VERSION 5.8 ;
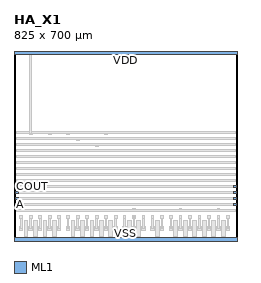
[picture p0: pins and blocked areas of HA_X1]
MACRO HA_X1
  CLASS CORE ;
  ORIGIN 0 0 ;
  SIZE 825 BY 700 ;
  SITE ICPS2023_5_ROW700 ;
  PIN A
    DIRECTION INPUT ;
    USE SIGNAL ;
    PORT
      LAYER ML1 ;
        RECT 5 130 15 140 ;
        RECT 810 130 820 140 ;
    END
  END A
  PIN B
    DIRECTION INPUT ;
    USE SIGNAL ;
    PORT
      LAYER ML1 ;
        RECT 5 152 15 162 ;
        RECT 810 152 820 162 ;
    END
  END B
  PIN SUM
    DIRECTION OUTPUT ;
    USE SIGNAL ;
    PORT
      LAYER ML1 ;
        RECT 5 174 15 184 ;
        RECT 810 174 820 184 ;
    END
  END SUM
  PIN COUT
    DIRECTION OUTPUT ;
    USE SIGNAL ;
    PORT
      LAYER ML1 ;
        RECT 5 196 15 206 ;
        RECT 810 196 820 206 ;
    END
  END COUT
  PIN VDD
    DIRECTION INOUT ;
    USE POWER ;
    PORT
      LAYER ML1 ;
        RECT 0 688 825 700 ;
    END
  END VDD
  PIN VSS
    DIRECTION INOUT ;
    USE GROUND ;
    PORT
      LAYER ML1 ;
        RECT 0 0 825 12 ;
    END
  END VSS
  OBS
    LAYER ML1 ;
      RECT 20 39.5 33 52.5 ;
      RECT 55 39.5 68 52.5 ;
      RECT 90 39.5 103 52.5 ;
      RECT 125 39.5 138 52.5 ;
      RECT 160 39.5 173 52.5 ;
      RECT 37.5 16 50.5 29 ;
      RECT 37.5 63 50.5 76 ;
      RECT 37 16 51 76 ;
      RECT 72.5 16 85.5 29 ;
      RECT 72.5 63 85.5 76 ;
      RECT 72 16 86 76 ;
      RECT 107.5 16 120.5 29 ;
      RECT 107.5 63 120.5 76 ;
      RECT 107 16 121 76 ;
      RECT 142.5 16 155.5 29 ;
      RECT 142.5 63 155.5 76 ;
      RECT 142 16 156 76 ;
      RECT 23.5 46 29.5 89 ;
      RECT 21.5 84 31.5 94 ;
      RECT 21.5 196 31.5 206 ;
      RECT 58.5 46 64.5 89 ;
      RECT 56.5 84 66.5 94 ;
      RECT 56.5 394 66.5 404 ;
      RECT 93.5 46 99.5 89 ;
      RECT 91.5 84 101.5 94 ;
      RECT 91.5 240 101.5 250 ;
      RECT 128.5 46 134.5 89 ;
      RECT 126.5 84 136.5 94 ;
      RECT 126.5 394 136.5 404 ;
      RECT 163.5 46 169.5 89 ;
      RECT 161.5 84 171.5 94 ;
      RECT 161.5 306 171.5 316 ;
      RECT 39 240 49 250 ;
      RECT 74 130 84 140 ;
      RECT 109 152 119 162 ;
      RECT 144 130 154 140 ;
      RECT 193 39.5 206 52.5 ;
      RECT 228 39.5 241 52.5 ;
      RECT 263 39.5 276 52.5 ;
      RECT 298 39.5 311 52.5 ;
      RECT 333 39.5 346 52.5 ;
      RECT 368 39.5 381 52.5 ;
      RECT 210.5 16 223.5 29 ;
      RECT 210.5 63 223.5 76 ;
      RECT 210 16 224 76 ;
      RECT 245.5 16 258.5 29 ;
      RECT 245.5 63 258.5 76 ;
      RECT 245 16 259 76 ;
      RECT 280.5 16 293.5 29 ;
      RECT 280.5 63 293.5 76 ;
      RECT 280 16 294 76 ;
      RECT 315.5 16 328.5 29 ;
      RECT 315.5 63 328.5 76 ;
      RECT 315 16 329 76 ;
      RECT 350.5 16 363.5 29 ;
      RECT 350.5 63 363.5 76 ;
      RECT 350 16 364 76 ;
      RECT 196.5 46 202.5 89 ;
      RECT 194.5 84 204.5 94 ;
      RECT 194.5 394 204.5 404 ;
      RECT 231.5 46 237.5 89 ;
      RECT 229.5 84 239.5 94 ;
      RECT 229.5 372 239.5 382 ;
      RECT 266.5 46 272.5 89 ;
      RECT 264.5 84 274.5 94 ;
      RECT 264.5 174 274.5 184 ;
      RECT 301.5 46 307.5 89 ;
      RECT 299.5 84 309.5 94 ;
      RECT 299.5 350 309.5 360 ;
      RECT 336.5 46 342.5 89 ;
      RECT 334.5 84 344.5 94 ;
      RECT 334.5 394 344.5 404 ;
      RECT 371.5 46 377.5 89 ;
      RECT 369.5 84 379.5 94 ;
      RECT 369.5 328 379.5 338 ;
      RECT 212 306 222 316 ;
      RECT 247 152 257 162 ;
      RECT 282 328 292 338 ;
      RECT 317 130 327 140 ;
      RECT 352 152 362 162 ;
      RECT 401 39.5 414 52.5 ;
      RECT 436 39.5 449 52.5 ;
      RECT 471 39.5 484 52.5 ;
      RECT 418.5 16 431.5 29 ;
      RECT 418.5 63 431.5 76 ;
      RECT 418 16 432 76 ;
      RECT 453.5 16 466.5 29 ;
      RECT 453.5 63 466.5 76 ;
      RECT 453 16 467 76 ;
      RECT 404.5 46 410.5 89 ;
      RECT 402.5 84 412.5 94 ;
      RECT 402.5 196 412.5 206 ;
      RECT 439.5 46 445.5 89 ;
      RECT 437.5 84 447.5 94 ;
      RECT 437.5 108 447.5 118 ;
      RECT 474.5 46 480.5 89 ;
      RECT 472.5 84 482.5 94 ;
      RECT 472.5 218 482.5 228 ;
      RECT 420 240 430 250 ;
      RECT 455 152 465 162 ;
      RECT 504 39.5 517 52.5 ;
      RECT 539 39.5 552 52.5 ;
      RECT 521.5 16 534.5 29 ;
      RECT 521.5 63 534.5 76 ;
      RECT 521 16 535 76 ;
      RECT 507.5 46 513.5 89 ;
      RECT 505.5 84 515.5 94 ;
      RECT 505.5 218 515.5 228 ;
      RECT 542.5 46 548.5 89 ;
      RECT 540.5 84 550.5 94 ;
      RECT 540.5 240 550.5 250 ;
      RECT 523 130 533 140 ;
      RECT 572 39.5 585 52.5 ;
      RECT 607 39.5 620 52.5 ;
      RECT 642 39.5 655 52.5 ;
      RECT 677 39.5 690 52.5 ;
      RECT 712 39.5 725 52.5 ;
      RECT 747 39.5 760 52.5 ;
      RECT 782 39.5 795 52.5 ;
      RECT 589.5 16 602.5 29 ;
      RECT 589.5 63 602.5 76 ;
      RECT 589 16 603 76 ;
      RECT 624.5 16 637.5 29 ;
      RECT 624.5 63 637.5 76 ;
      RECT 624 16 638 76 ;
      RECT 659.5 16 672.5 29 ;
      RECT 659.5 63 672.5 76 ;
      RECT 659 16 673 76 ;
      RECT 694.5 16 707.5 29 ;
      RECT 694.5 63 707.5 76 ;
      RECT 694 16 708 76 ;
      RECT 729.5 16 742.5 29 ;
      RECT 729.5 63 742.5 76 ;
      RECT 729 16 743 76 ;
      RECT 764.5 16 777.5 29 ;
      RECT 764.5 63 777.5 76 ;
      RECT 764 16 778 76 ;
      RECT 575.5 46 581.5 89 ;
      RECT 573.5 84 583.5 94 ;
      RECT 573.5 306 583.5 316 ;
      RECT 610.5 46 616.5 89 ;
      RECT 608.5 84 618.5 94 ;
      RECT 608.5 108 618.5 118 ;
      RECT 645.5 46 651.5 89 ;
      RECT 643.5 84 653.5 94 ;
      RECT 643.5 262 653.5 272 ;
      RECT 680.5 46 686.5 89 ;
      RECT 678.5 84 688.5 94 ;
      RECT 678.5 174 688.5 184 ;
      RECT 715.5 46 721.5 89 ;
      RECT 713.5 84 723.5 94 ;
      RECT 713.5 284 723.5 294 ;
      RECT 750.5 46 756.5 89 ;
      RECT 748.5 84 758.5 94 ;
      RECT 748.5 108 758.5 118 ;
      RECT 785.5 46 791.5 89 ;
      RECT 783.5 84 793.5 94 ;
      RECT 783.5 328 793.5 338 ;
      RECT 591 130 601 140 ;
      RECT 626 152 636 162 ;
      RECT 661 130 671 140 ;
      RECT 696 306 706 316 ;
      RECT 731 328 741 338 ;
      RECT 766 152 776 162 ;
      RECT 10 110 815 116 ;
      RECT 10 132 815 138 ;
      RECT 10 154 815 160 ;
      RECT 10 176 815 182 ;
      RECT 10 198 815 204 ;
      RECT 10 220 815 226 ;
      RECT 10 242 815 248 ;
      RECT 10 264 815 270 ;
      RECT 10 286 815 292 ;
      RECT 10 308 815 314 ;
      RECT 10 330 815 336 ;
      RECT 10 352 815 358 ;
      RECT 10 374 815 380 ;
      RECT 10 396 815 402 ;
      RECT 439.5 3 445.5 92 ;
      RECT 58.5 396 64.5 697 ;
  END
END HA_X1
